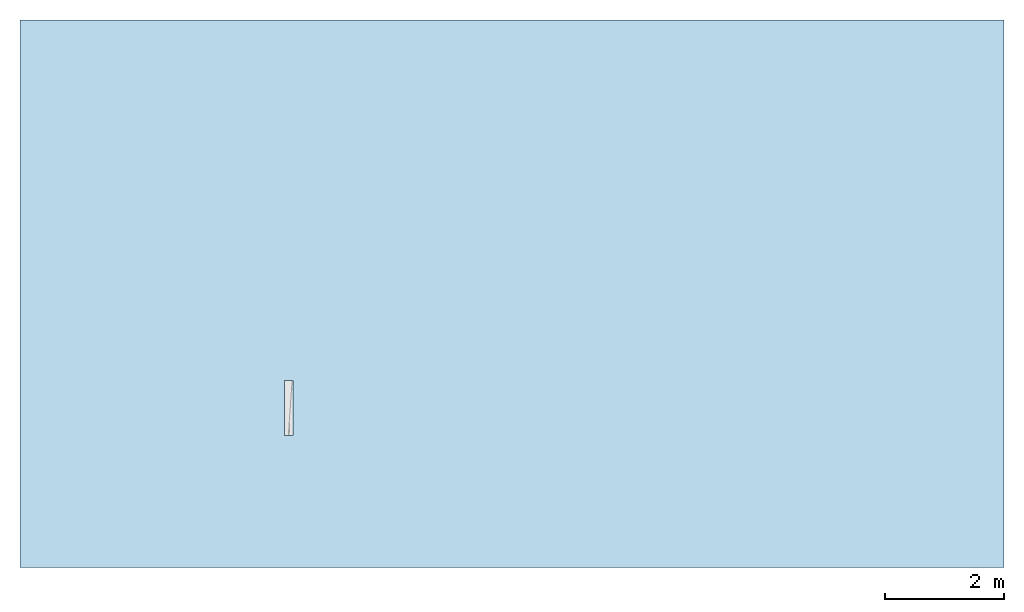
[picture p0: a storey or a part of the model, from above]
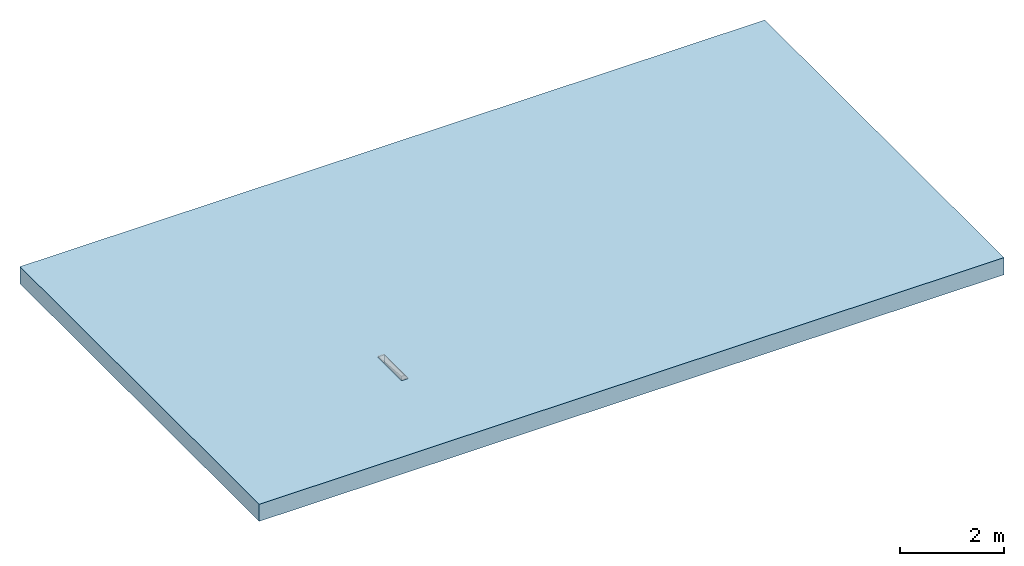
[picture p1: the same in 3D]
Properties of the parts of a building model (IFC2X3)

# File
Description: ViewDefinition [CoordinationView]
File name: 7938 - LH drop kerb - 1000mm LG.ifc
Time: 2013-09-02T12:31:58
Written by: Autodesk Revit 2013
Made in: 20120221_2030(x64)

# IfcProject, Project Number
LongName: Project Name; Phase: Project Status

# IfcSite, Default
RefLatitude: 42, 21, 30, 344238; RefLongitude: -71, -3, -35, -194702; RefElevation: 0 mm

# IfcBuilding
Pset_BuildingCommon - NumberOfStoreys: 1
Other - Project Status: Project Status; Project Number: Project Number; Project Name: Project Name; Project Address: ## Street City, State Zip; Project Issue Date: Issue Date; Client Name: Owner

# IfcBuildingStorey, Level 1
LongName: Level 1; Elevation: 0 mm
Constraints - Elevation Base: 0; Elevation: 0 mm
Graphics - Symbol: M_Level Head - Circle: M_Level Head - Circle; Symbol at End 2 Default: yes; Line Pattern: Center; Line Weight: 1; Symbol at End 1 Default: no; Color: 0
Identity Data - Building Story: yes; Structural: no; Name: Level 1
Dimensions - Computation Height: 0 mm

# IfcBuildingElementProxy: 7938 - LH drop kerb - 1000mm LG, Civil-Drainage-Channel-ACO-KerbDrain-SP280:7938 - LH drop kerb - 1000mm LG:7938 - LH drop kerb - 1000mm LG:311063
In: Level 1
Material: ACO Polymer Concrete.
Dimensions - Volume: 21613105 mm3; AccessDepth: 2000 mm; Void Depth: -180 mm; Endcap void: 205 mm; Void Width: 150 mm; Access hole: 2 mm; Void Length: 915 mm
Constraints - Level: Level: Level 1; Moves With Nearby Elements: no
Phasing - Phase Created: New Construction
Pset_BuildingElementProxyCommon - Reference: 7938 - LH drop kerb - 1000mm LG
Materials and Finishes - Channel Material: Vienite® Synthetic Resin Concrete; End Cap Colour: N/A; Connection Pipe Material Colour: N/A; Connection Pipe Material: N/A; Access Cover/Frame Finish: N/A; Channel Colour: Grey; Access Cover/Frame Colour: N/A; Access Cover/Frame Material: N/A; End Cap Material: N/A
Data - Hydraulic Performance: http://www.aco.co.uk/download.php?id=120; Load Class: A 15 - D 400; Product Dimensions: 1000mm x 150mm x 380/305mm (LxWxH); Connection Pipe O.D: N/A; Drainage Slot Width: N/A; Product Weight: 44.6 Kg; Channel C.S.A: 0.02 to 0.008m²; Concrete Surround Volume - Load Class A 15 - D 400 - Grass or Asphalt Pavement: N/A; Installation - Concrete Grade: Refer to brochure; Concrete Surround Volume - Load Class A 15 - D 400 - Concrete Pavement: N/A; Invert Depth: 255/180mm; Product Standard: BS EN 1433:2002, CE marked, Kitemarked; Drainage Slot Intake area: N/A; ACO Hydraulic Design Software: http://www.acodesign.co.uk
Identity Data - Assembly Code: D2040; Maintenance guidelines: http://www.aco.co.uk/download.php?id=120; Product Page URL: http://www.aco.co.uk/product_detail.php?id=3; Telephone: +44 (0)1462 816666; Installation guidelines: http://www.aco.co.uk/download.php?id=120; URL: www.aco.co.uk; Manufacturer: ACO Technologies plc - ACO Water Management Division; Product Code: 7938; Assembly Description: Rain Water Drainage; OmniClass Number: 23.70.50.24; OmniClass Title: Rainwater Removal; Price: POA - contact ACO; Model: ACO KerbDrain SP280; Fax: +44 (0)1462 815895; Product brochure: http://www.aco.co.uk/download.php?id=120; Model Description: Combined kerb and drainage system; e-mail Sales: customersupport@aco.co.uk; Cost: 0; Address: ACO Business Park, Hitchin Road, Shefford, Bedfordshire, United Kingdom SG17 5TE; Type Comments: ACO KerbDrain SP280 splayed left-hand drop kerb unit 1000mm long; e-mail Technical: technical@aco.co.uk
Construction - Closing end cap: no; Access Unit: no; RH transition unit: no; LH transition unit: no; LH drop kerb: yes; SP280 - 1000: no; RH inlet/outlet end cap: no; perforated centre stone: no; RH drop kerb: no; LH inlet/outlet end cap: no; Centre Stone: no; SP280-500: no
General - TagNumber: 0.000000; SerialNumber: 0.000000
Other - CreatedBy: www.aco.co.uk; Revision: 1
Green Building Properties - End Cap Recyclable: N/A; Access Cover/Frame Recyclable: N/A; End Cap Recycled Material Content: N/A; Channel Recyclable: Fully recyclable; Channel Recycled Material Content: 20% minimum; Access Cover/Frame Recycled Material Content: N/A

# IfcOpeningElement: Recess (2)
In: Level 1
Dimensions - Thickness: 400 mm; Perimeter: 51360 mm; Area: 151470000 mm2; Volume: 60563295000 mm3
Phasing - Phase Created: New Construction
Constraints - Height Offset From Level: 0 mm; Room Bounding: yes; Related to Mass: no; Level: Level: Level 1
Structural - Enable Analytical Model: no; Structural: no
Graphics - Coarse Scale Fill Color: 0
Materials and Finishes - Structural Material: Plant
Analytical Properties - Roughness: 1; Absorptance: 0.1
Construction - Default Thickness: 400 mm; Function: 0

# IfcSlab: Floor:Generic Floor - 400mm, Floor:Generic Floor - 400mm:193825
In: Level 1
PredefinedType: FLOOR; Material: Plant 400 mm
Dimensions - Thickness: 400 mm; Perimeter: 51360 mm; Area: 151470000 mm2; Volume: 60563295000 mm3
Phasing - Phase Created: New Construction
Constraints - Height Offset From Level: 0 mm; Room Bounding: yes; Related to Mass: no; Level: Level: Level 1
Structural - Enable Analytical Model: no; Structural: no
Pset_SlabCommon - Reference: Generic Floor - 400mm; IsExternal: no; LoadBearing: yes
Graphics - Coarse Scale Fill Color: 0
Materials and Finishes - Structural Material: Plant
Analytical Properties - Roughness: 1; Absorptance: 0.1
Construction - Default Thickness: 400 mm; Function: 0
